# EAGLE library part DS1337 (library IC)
310110008

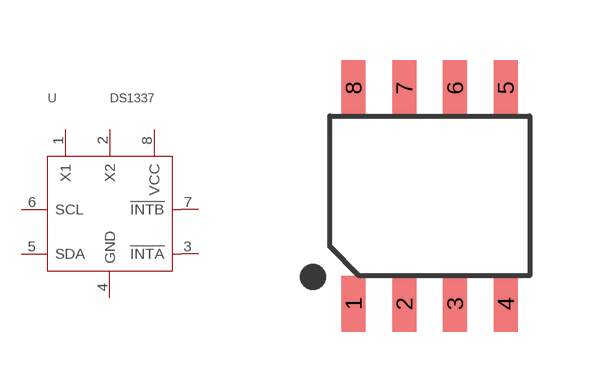
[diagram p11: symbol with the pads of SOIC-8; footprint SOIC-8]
Designator prefix U

## DS1337-DS1337S  [SOIC-8]
1  X1
2  X2
3  !INTA!
4  GND
5  SDA
6  SCL
7  !INTB!
8  VCC

## Footprint SOIC-8 (pad centres in mm)
smd 0.6 x 1.4: 1 -1.905,-2.7; 2 -0.635,-2.7; 3 0.635,-2.7; 4 1.905,-2.7; 5 1.905,2.7; 6 0.635,2.7; 7 -0.635,2.7; 8 -1.905,2.7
